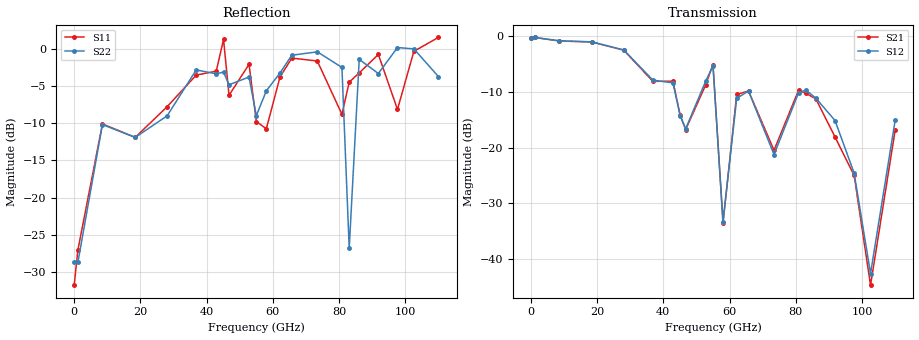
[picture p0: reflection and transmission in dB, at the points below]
!Keysight Technologies,N5247B,US61255204,A.15.70.20
!Date: Friday, October 21, 2022 14:07:45
!Correction: S11(C  4-Port  )
!S31(C  4-Port  )
!S13(C  4-Port  )
!S33(C  4-Port  )
!S2P File: Measurements: S11, S31, S13, S33:
# Hz S  dB  R 50
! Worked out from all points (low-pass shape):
!   401 points, 10 MHz to 110 GHz, reference 50 ohm
!   highest |S21| = -0.22 dB at 1.11 GHz (marker M1); lowest = -44.7 dB at 102.6 GHz (marker M2)
!   |S21| within 3 dB of the highest: start of sweep to 31.87 GHz
!   lowest |S11| = -31.8 dB at 10 MHz (marker M3), VSWR 1.05, Z = 52.6 + j0.106 ohm
!   |S11| at or under -10 dB: start of sweep to 8.657 GHz; 15.83 GHz to 22.3 GHz (6.473 GHz wide, 34 % of centre); 29.97 GHz to 31.37 GHz (1.396 GHz wide, 4.55 % of centre) (the widest 3 of 7)
!   |S22| runs from -38.0 to 0.2 dB; largest |S21 - S12| = 0.15
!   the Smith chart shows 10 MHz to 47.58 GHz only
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1e7  -31.81 2.2  -0.30 -0.2  -0.30 -0.0  -28.64 -2.0
1.1099e9  -27.11 70.7  -0.22 -1.4  -0.20 -1.3  -28.76 113.5
8.534225e9  -10.08 80.5  -0.84 -10.6  -0.81 -10.5  -10.16 78.8
1.843332e10  -11.89 73.3  -1.04 -23.2  -1.00 -22.9  -11.90 70.4
2.805745e10  -7.76 64.3  -2.50 -55.3  -2.46 -53.9  -8.99 41.3
3.685665e10  -3.49 149.3  -8.10 -100.1  -7.88 -99.9  -2.80 166.1
4.29061e10  -2.97 125.3  -8.07 -115.8  -8.37 -115.3  -3.32 153.5
4.51059e10  1.32 76.2  -14.20 -154.2  -14.30 -156.4  -3.09 84.7
4.675575e10  -6.22 65.9  -16.78 -54.4  -16.61 -50.7  -4.80 32.3
5.28052e10  -2.04 110.9  -8.72 -134.4  -8.06 -133.2  -3.76 137.7
5.5005e10  -9.77 179.8  -5.08 161.0  -5.27 160.7  -8.96 151.6
5.802972e10  -10.72 159.8  -33.58 147.7  -33.29 147.0  -5.61 172.6
6.215435e10  -3.74 78.7  -10.46 -164.5  -11.17 -158.9  -3.20 -177.4
6.572902e10  -1.20 13.8  -9.82 129.3  -9.83 149.9  -0.81 34.1
7.342832e10  -1.60 127.5  -20.49 34.5  -21.25 32.6  -0.36 114.8
8.085265e10  -8.78 -91.0  -9.68 20.2  -10.14 20.6  -2.46 -141.4
8.305245e10  -4.45 -47.2  -10.25 -42.6  -9.67 -25.7  -26.84 135.8
8.607718e10  -3.20 6.6  -11.24 -49.2  -11.13 -48.0  -1.38 -14.7
9.185165e10  -0.71 72.4  -18.10 -92.5  -15.14 -89.0  -3.28 68.0
9.762612e10  -8.12 177.6  -24.99 163.0  -24.58 160.9  0.22 167.0
1.025757e11  -0.29 -79.8  -44.71 173.4  -42.64 -174.6  0.04 -117.0
1.1e11  1.59 9.1  -16.92 -158.6  -15.13 -163.7  -3.70 15.4
